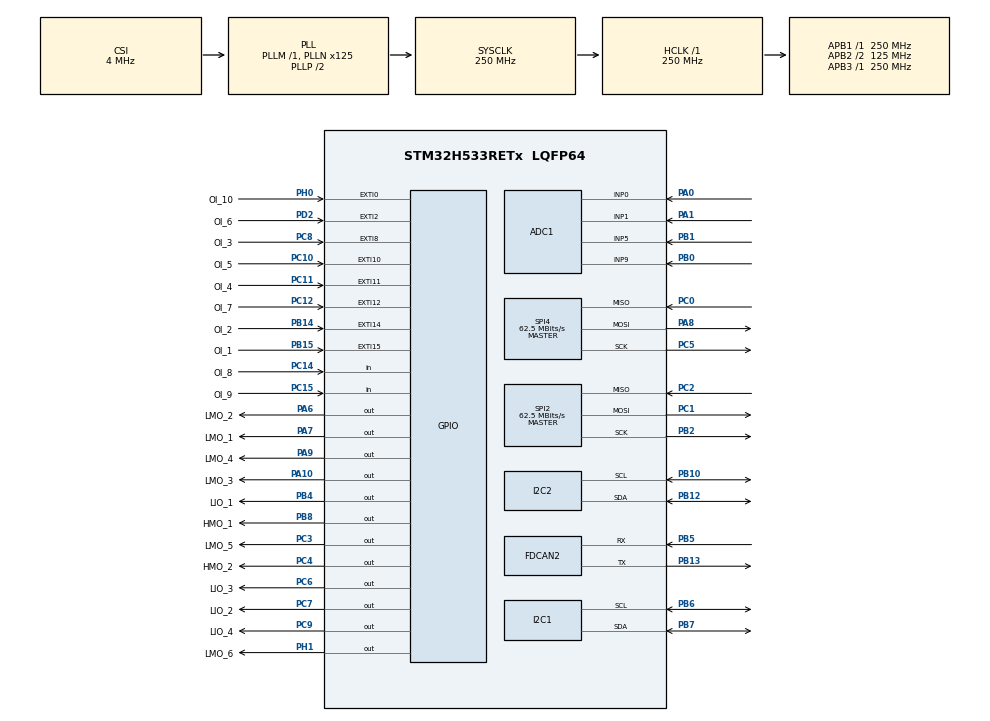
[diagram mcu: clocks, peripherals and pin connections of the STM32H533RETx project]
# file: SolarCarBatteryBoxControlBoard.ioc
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ADC1.Channel-2\#ChannelRegularConversion=ADC_CHANNEL_0
ADC1.Channel-3\#ChannelRegularConversion=ADC_CHANNEL_1
ADC1.Channel-4\#ChannelRegularConversion=ADC_CHANNEL_5
ADC1.Channel-5\#ChannelRegularConversion=ADC_CHANNEL_9
ADC1.DiscontinuousConvMode=DISABLE
ADC1.EOCSelection=ADC_EOC_SEQ_CONV
ADC1.EnableAnalogWatchDog1=false
ADC1.ExternalTrigConv=ADC_SOFTWARE_START
ADC1.MonitoredBy-2\#ChannelRegularConversion=__NULL
ADC1.MonitoredBy-3\#ChannelRegularConversion=__NULL
ADC1.MonitoredBy-4\#ChannelRegularConversion=__NULL
ADC1.MonitoredBy-5\#ChannelRegularConversion=__NULL
ADC1.NbrOfConversion=4
ADC1.NbrOfConversionFlag=1
ADC1.OffsetNumber-2\#ChannelRegularConversion=ADC_OFFSET_NONE
ADC1.OffsetNumber-3\#ChannelRegularConversion=ADC_OFFSET_NONE
ADC1.OffsetNumber-4\#ChannelRegularConversion=ADC_OFFSET_NONE
ADC1.OffsetNumber-5\#ChannelRegularConversion=ADC_OFFSET_NONE
ADC1.Overrun=ADC_OVR_DATA_PRESERVED
ADC1.OversamplingMode=DISABLE
ADC1.Rank-2\#ChannelRegularConversion=1
ADC1.Rank-3\#ChannelRegularConversion=2
ADC1.Rank-4\#ChannelRegularConversion=3
ADC1.Rank-5\#ChannelRegularConversion=4
ADC1.SamplingTime-2\#ChannelRegularConversion=ADC_SAMPLETIME_24CYCLES_5
ADC1.SamplingTime-3\#ChannelRegularConversion=ADC_SAMPLETIME_24CYCLES_5
ADC1.SamplingTime-4\#ChannelRegularConversion=ADC_SAMPLETIME_24CYCLES_5
ADC1.SamplingTime-5\#ChannelRegularConversion=ADC_SAMPLETIME_24CYCLES_5
ADC1.master=1
BOOTPATH.BootPathName=LEGACY
BOOTPATH.UserSelectedBootPath=LEGACY
CORTEX_M33_NS.Enable-Cortex_Memory_Protection_Unit_Region0_Settings=__NULL
CORTEX_M33_NS.MPU_Control=__NULL
CORTEX_M33_NS.Number-Cortex_Memory_Protection_Unit_Region0_Settings=MPU_REGION_NUMBER0
CORTEX_M33_NS.userName=CORTEX_M33
FDCAN2.AutoRetransmission=ENABLE
FDCAN2.CalculateBaudRateNominal=500000
FDCAN2.CalculateTimeBitNominal=2000
FDCAN2.CalculateTimeQuantumNominal=250.0
FDCAN2.FrameFormat=FDCAN_FRAME_FD_NO_BRS
FDCAN2.Mode=FDCAN_MODE_NORMAL
FDCAN2.NominalPrescaler=32
FDCAN2.NominalTimeSeg1=6
FDCAN2.NominalTimeSeg2=1
FDCAN2.StdFiltersNbr=0
GPDMA1.CIRCULARMODE_GPDMACH0=ENABLE
GPDMA1.DATAHANDLING_GPDMACH0=NONE
GPDMA1.DESTDATAWIDTH_GPDMACH0=DMA_DEST_DATAWIDTH_HALFWORD
GPDMA1.DESTINC_GPDMACH0=DMA_DINC_INCREMENTED
GPDMA1.IPHANDLE_GPDMACH0-SIMPLEREQUEST_GPDMACH0=__NULL
GPDMA1.REQUEST_GPDMACH0=GPDMA1_REQUEST_ADC1
GPDMA1.SRCDATAWIDTH_GPDMACH0=DMA_SRC_DATAWIDTH_HALFWORD
GPDMA1.TRIGGERPOLARITY_GPDMACH0=DMA_TRIG_POLARITY_MASKED
I2C1.Timing=0x60808CD3
I2C2.Timing=0x60808CD3
Mcu.Family=STM32H5
Mcu.Name=STM32H533RETx
Mcu.Package=LQFP64
NUCLEO-H533RE.BUTTON=1
NUCLEO-H533RE.LD4=true
NUCLEO-H533RE.VCP=true
NVIC.EXTI0_IRQn=true\:2\:0\:true\:false\:true\:true\:true\:true
NVIC.EXTI10_IRQn=true\:2\:0\:true\:false\:true\:true\:true\:true
NVIC.EXTI11_IRQn=true\:2\:0\:true\:false\:true\:true\:true\:true
NVIC.EXTI12_IRQn=true\:2\:0\:true\:false\:true\:true\:true\:true
NVIC.EXTI13_IRQn=true\:2\:0\:true\:false\:true\:true\:true\:true
NVIC.EXTI14_IRQn=true\:2\:0\:true\:false\:true\:true\:true\:true
NVIC.EXTI15_IRQn=true\:2\:0\:true\:false\:true\:true\:true\:true
NVIC.EXTI2_IRQn=true\:2\:0\:true\:false\:true\:true\:true\:true
NVIC.EXTI8_IRQn=true\:2\:0\:true\:false\:true\:true\:true\:true
NVIC.FDCAN2_IT0_IRQn=true\:2\:0\:true\:false\:true\:true\:true\:true
NVIC.GPDMA1_Channel0_IRQn=true\:0\:0\:false\:false\:true\:false\:true\:true
NVIC.I2C1_ER_IRQn=true\:0\:0\:false\:false\:true\:true\:true\:true
NVIC.I2C1_EV_IRQn=true\:0\:0\:true\:false\:true\:true\:true\:true
NVIC.PriorityGroup=NVIC_PRIORITYGROUP_4
PA0.Signal=ADCx_INP0
PA1.Signal=ADCx_INP1
PA10.GPIO_Label=LMO_3
PA10.Signal=GPIO_Output
PA13(JTMS/SWDIO).GPIO_Label=SWDIO
PA13(JTMS/SWDIO).Signal=DEBUG_JTMS-SWDIO
PA14(JTCK/SWCLK).GPIO_Label=SWCLK
PA14(JTCK/SWCLK).Signal=DEBUG_JTCK-SWCLK
PA15(JTDI).GPIO_Label=JTDI
PA15(JTDI).Signal=DEBUG_JTDI
PA2.Signal=USART2_TX
PA3.Signal=USART2_RX
PA6.GPIO_Label=LMO_2
PA6.Signal=GPIO_Output
PA7.GPIO_Label=LMO_1
PA7.Signal=GPIO_Output
PA8.GPIO_Speed=GPIO_SPEED_FREQ_VERY_HIGH
PA8.Mode=Full_Duplex_Master
PA8.Signal=SPI4_MOSI
PA9.GPIO_Label=LMO_4
PA9.Signal=GPIO_Output
PB0.Signal=ADCx_INP9
PB1.Signal=ADCx_INP5
PB10.GPIO_Pu=GPIO_PULLUP
PB10.GPIO_Speed=GPIO_SPEED_FREQ_VERY_HIGH
PB10.Mode=I2C
PB10.Signal=I2C2_SCL
PB12.GPIO_Pu=GPIO_PULLUP
PB12.GPIO_Speed=GPIO_SPEED_FREQ_VERY_HIGH
PB12.Mode=I2C
PB12.Signal=I2C2_SDA
PB13.GPIO_Speed=GPIO_SPEED_FREQ_VERY_HIGH
PB13.Mode=FDCAN_Activate
PB13.Signal=FDCAN2_TX
PB14.GPIO_Label=OI_2
PB14.GPIO_ModeDefaultEXTI=GPIO_MODE_IT_RISING_FALLING
PB14.Signal=GPXTI14
PB15.GPIO_Label=OI_1
PB15.GPIO_ModeDefaultEXTI=GPIO_MODE_IT_RISING_FALLING
PB15.GPIO_PuPd=GPIO_NOPULL
PB15.Signal=GPXTI15
PB2.GPIO_Speed=GPIO_SPEED_FREQ_VERY_HIGH
PB2.Mode=Full_Duplex_Master
PB2.Signal=SPI2_SCK
PB3(JTDO/TRACESWO).GPIO_Label=SWO
PB3(JTDO/TRACESWO).Signal=DEBUG_JTDO-SWO
PB4(NJTRST).GPIO_Label=LIO_1
PB4(NJTRST).Signal=GPIO_Output
PB5.GPIO_PuPd=GPIO_PULLUP
PB5.GPIO_Speed=GPIO_SPEED_FREQ_VERY_HIGH
PB5.Mode=FDCAN_Activate
PB5.Signal=FDCAN2_RX
PB6.GPIO_Pu=GPIO_PULLUP
PB6.GPIO_Speed=GPIO_SPEED_FREQ_VERY_HIGH
PB6.Mode=I2C
PB6.Signal=I2C1_SCL
PB7.GPIO_Pu=GPIO_PULLUP
PB7.GPIO_Speed=GPIO_SPEED_FREQ_VERY_HIGH
PB7.Mode=I2C
PB7.Signal=I2C1_SDA
PB8.GPIO_Label=HMO_1
PB8.GPIO_PuPd=GPIO_PULLUP
PB8.PinState=GPIO_PIN_SET
PB8.Signal=GPIO_Output
PC0.GPIO_Speed=GPIO_SPEED_FREQ_VERY_HIGH
PC0.Mode=Full_Duplex_Master
PC0.Signal=SPI4_MISO
PC1.GPIO_Speed=GPIO_SPEED_FREQ_VERY_HIGH
PC1.Mode=Full_Duplex_Master
PC1.Signal=SPI2_MOSI
PC10.GPIO_Label=OI_5
PC10.GPIO_ModeDefaultEXTI=GPIO_MODE_IT_RISING_FALLING
PC10.Signal=GPXTI10
PC11.GPIO_Label=OI_4
PC11.GPIO_ModeDefaultEXTI=GPIO_MODE_IT_RISING_FALLING
PC11.Signal=GPXTI11
PC12.GPIO_Label=OI_7
PC12.GPIO_ModeDefaultEXTI=GPIO_MODE_IT_RISING_FALLING
PC12.Signal=GPXTI12
PC14-OSC32_IN(OSC32_IN).GPIO_Label=OI_8
PC14-OSC32_IN(OSC32_IN).Signal=GPIO_Input
PC15-OSC32_OUT(OSC32_OUT).GPIO_Label=OI_9
PC15-OSC32_OUT(OSC32_OUT).Signal=GPIO_Input
PC2.GPIO_Speed=GPIO_SPEED_FREQ_VERY_HIGH
PC2.Mode=Full_Duplex_Master
PC2.Signal=SPI2_MISO
PC3.GPIO_Label=LMO_5
PC3.Signal=GPIO_Output
PC4.GPIO_Label=HMO_2
PC4.GPIO_PuPd=GPIO_PULLUP
PC4.PinState=GPIO_PIN_SET
PC4.Signal=GPIO_Output
PC5.GPIO_Speed=GPIO_SPEED_FREQ_VERY_HIGH
PC5.Mode=Full_Duplex_Master
PC5.Signal=SPI4_SCK
PC6.GPIO_Label=LIO_3
PC6.Signal=GPIO_Output
PC7.GPIO_Label=LIO_2
PC7.Signal=GPIO_Output
PC8.GPIO_Label=OI_3
PC8.GPIO_ModeDefaultEXTI=GPIO_MODE_IT_RISING_FALLING
PC8.GPIO_PuPd=GPIO_NOPULL
PC8.Signal=GPXTI8
PC9.GPIO_Label=LIO_4
PC9.Signal=GPIO_Output
PD2.GPIO_Label=OI_6
PD2.GPIO_ModeDefaultEXTI=GPIO_MODE_IT_RISING_FALLING
PD2.Signal=GPXTI2
PH0-OSC_IN(PH0).GPIO_Label=OI_10
PH0-OSC_IN(PH0).GPIO_ModeDefaultEXTI=GPIO_MODE_IT_RISING_FALLING
PH0-OSC_IN(PH0).Signal=GPXTI0
PH1-OSC_OUT(PH1).GPIO_Label=LMO_6
PH1-OSC_OUT(PH1).Signal=GPIO_Output
ProjectManager.HeapSize=0x200
ProjectManager.StackSize=0x400
ProjectManager.TargetToolchain=CMake
RCC.ADCFreq_Value=250000000
RCC.AHBFreq_Value=250000000
RCC.APB1Freq_Value=250000000
RCC.APB1TimFreq_Value=250000000
RCC.APB2CLKDivider=RCC_HCLK_DIV2
RCC.APB2Freq_Value=125000000
RCC.APB2TimFreq_Value=250000000
RCC.APB3Freq_Value=250000000
RCC.CSI_VALUE=4000000
RCC.CortexFreq_Value=250000000
RCC.EPOD_VALUE=4000000
RCC.FDCANClockSelection=RCC_FDCANCLKSOURCE_PLL2Q
RCC.HCLKFreq_Value=250000000
RCC.HSE_VALUE=25000000
RCC.HSI48_VALUE=48000000
RCC.HSIDiv=RCC_HSI_DIV1
RCC.HSI_VALUE=64000000
RCC.LSE_VALUE=32768
RCC.LSIRC_VALUE=32000
RCC.PLL1Q=4
RCC.PLL2FRACN=0
RCC.PLL2N=32
RCC.PLL2Q=1
RCC.PLL3N=128
RCC.PLLFRACN=0
RCC.PLLN=125
RCC.SYSCLKFreq_VALUE=250000000
RCC.SYSCLKSource=RCC_SYSCLKSOURCE_PLLCLK
RCC.USBFreq_Value=48000000
RCC.VCOOutputFreq_Value=500000000
SH.ADCx_INP0.0=ADC1_INP0,IN0-Single-Ended
SH.ADCx_INP1.0=ADC1_INP1,IN1-Single-Ended
SH.ADCx_INP5.0=ADC1_INP5,IN5-Single-Ended
SH.ADCx_INP9.0=ADC1_INP9,IN9-Single-Ended
SPI2.BaudRatePrescaler=SPI_BAUDRATEPRESCALER_2
SPI2.CalculateBaudRate=62.5 MBits/s
SPI2.Direction=SPI_DIRECTION_2LINES
SPI2.Mode=SPI_MODE_MASTER
SPI2.VirtualType=VM_MASTER
SPI4.CalculateBaudRate=62.5 MBits/s
SPI4.Direction=SPI_DIRECTION_2LINES
SPI4.Mode=SPI_MODE_MASTER
SPI4.VirtualType=VM_MASTER
VP_BOOTPATH_VS_BOOTPATH.Mode=BP_Activate
VP_CORTEX_M33_NS_VS_Hclk.Mode=Hclk_Mode
VP_GPDMA1_VS_GPDMACH0.Mode=SIMPLEREQUEST_GPDMACH0
VP_ICACHE_VS_ICACHE.Mode=DefaultMode
VP_MEMORYMAP_VS_MEMORYMAP.Mode=CurAppReg
VP_NUCLEO-H533RE_VS_BSP_COMMON.Mode=COMMON
VP_PWR_VS_LPOM.Mode=PowerOptimisation
VP_PWR_VS_SECSignals.Mode=Security/Privilege
board=NUCLEO-H533RE

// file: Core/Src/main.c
/* USER CODE BEGIN Header */
/**
 ******************************************************************************
 * @file           : main.c
 * @brief          : Main program body
 ******************************************************************************
 * @attention
 *
 * Copyright (c) 2026 STMicroelectronics.
 * All rights reserved.
 *
 * This software is licensed under terms that can be found in the LICENSE file
 * in the root directory of this software component.
 * If no LICENSE file comes with this software, it is provided AS-IS.
 *
 ******************************************************************************
 */
/* USER CODE END Header */
#include "main.h"

/* USER CODE BEGIN Includes */
#include "stm32h5xx_hal.h"
#include "stm32h5xx_hal_fdcan.h"
#include "stm32h5xx_nucleo.h"
#include "ws_can_comms.h"
#include <stdint.h>
#include <string.h>
/* USER CODE END Includes */

COM_InitTypeDef BspCOMInit;
ADC_HandleTypeDef hadc1;

FDCAN_HandleTypeDef hfdcan2;

I2C_HandleTypeDef hi2c1;
I2C_HandleTypeDef hi2c2;

SPI_HandleTypeDef hspi2;
SPI_HandleTypeDef hspi4;

void SystemClock_Config(void);
static void MX_GPIO_Init(void);
static void MX_FDCAN2_Init(void);
static void MX_I2C1_Init(void);
static void MX_I2C2_Init(void);
static void MX_SPI2_Init(void);
static void MX_SPI4_Init(void);
static void MX_ICACHE_Init(void);
static void MX_ADC1_Init(void);

/* USER CODE BEGIN 0 */

// FDCAN2 Defines
FDCAN_TxHeaderTypeDef txHeader;
FDCAN_RxHeaderTypeDef rxHeader;
uint8_t txData[64];
uint8_t rxData[8];

void HAL_FDCAN_RxFifo0Callback(FDCAN_HandleTypeDef *hfdcan,
                               uint32_t RxFifo0ITs) {
  if ((RxFifo0ITs & FDCAN_IT_RX_FIFO0_NEW_MESSAGE) != RESET) {
    /* Retreive Rx messages from RX FIFO0 */
    if (HAL_FDCAN_GetRxMessage(hfdcan, FDCAN_RX_FIFO0, &rxHeader, rxData) !=
        HAL_OK) {
      /* Reception Error */
      Error_Handler();
    }
    if (HAL_FDCAN_ActivateNotification(hfdcan, FDCAN_IT_RX_FIFO0_NEW_MESSAGE,
                                       0) != HAL_OK) {
      /* Notification Error */
      Error_Handler();
    }

    // Just for testing purposes
    uint32_t data1, data2;
    memcpy(&data1, &rxData[0], sizeof(data1));
    memcpy(&data2, &rxData[4], sizeof(data2));

    printf("\n\nID:0x%x/n%.8lx 0x%.8lx\n\n",rxHeader.Identifier, data1, data2);
  }
}

/* USER CODE END 0 */

int main(void) {

  /* MCU Configuration--------------------------------------------------------*/

  /* Reset of all peripherals, Initializes the Flash interface and the Systick.
   */
  HAL_Init();

  /* Configure the system clock */
  SystemClock_Config();

  /* Initialize all configured peripherals */
  MX_GPIO_Init();
  MX_FDCAN2_Init();
  MX_I2C1_Init();
  MX_I2C2_Init();
  MX_SPI2_Init();
  MX_SPI4_Init();
  MX_ICACHE_Init();
  MX_ADC1_Init();
  /* USER CODE BEGIN 2 */

  // Start FDCAN2
  if (HAL_FDCAN_Start(&hfdcan2) != HAL_OK) {
    Error_Handler();
  }
  // Activate FIFO0 reciept notification
  if (HAL_FDCAN_ActivateNotification(&hfdcan2, FDCAN_IT_RX_FIFO0_NEW_MESSAGE,
                                     0) != HAL_OK) {
    /* Notification Error */
    Error_Handler();
  }

  // Configure TX Header for FDCAN2
  txHeader.Identifier = 0x11;
  txHeader.IdType = FDCAN_STANDARD_ID;
  txHeader.TxFrameType = FDCAN_DATA_FRAME;
  txHeader.DataLength = FDCAN_DLC_BYTES_8;
  txHeader.ErrorStateIndicator = FDCAN_ESI_ACTIVE;
  txHeader.BitRateSwitch = FDCAN_BRS_OFF;
  txHeader.FDFormat = FDCAN_CLASSIC_CAN;
  txHeader.TxEventFifoControl = FDCAN_NO_TX_EVENTS;
  txHeader.MessageMarker = 0;

  /* USER CODE END 2 */

  /* Initialize leds */
  BSP_LED_Init(LED_GREEN);

  /* Initialize USER push-button, will be used to trigger an interrupt each time
   * it's pressed.*/
  BSP_PB_Init(BUTTON_USER, BUTTON_MODE_EXTI);

  /* Initialize COM1 port (115200, 8 bits (7-bit data + 1 stop bit), no parity
   */
  BspCOMInit.BaudRate = 115200;
  BspCOMInit.WordLength = COM_WORDLENGTH_8B;
  BspCOMInit.StopBits = COM_STOPBITS_1;
  BspCOMInit.Parity = COM_PARITY_NONE;
  BspCOMInit.HwFlowCtl = COM_HWCONTROL_NONE;
  if (BSP_COM_Init(COM1, &BspCOMInit) != BSP_ERROR_NONE) {
    Error_Handler();
  }

  /* Infinite loop */
  while (1) {

    /* USER CODE BEGIN 3 */
    // Blink to show alive
    BSP_LED_Toggle(LED_GREEN);

    WS_RequestIdentificationInformation(&hfdcan2);
    // Should result in the serial number and Prohelion ID being sent to CAN Bus
    // After the message is received, the expected output is:
    // <Serial number>
    // 0x00004003 (Prohelion ID)

    HAL_Delay(2500);
    // Blink to show alive
    BSP_LED_Toggle(LED_GREEN);
    HAL_Delay(2500);
  }
  /* USER CODE END 3 */
}

void SystemClock_Config(void) {
  RCC_OscInitTypeDef RCC_OscInitStruct = {0};
  RCC_ClkInitTypeDef RCC_ClkInitStruct = {0};

  /** Configure the main internal regulator output voltage
   */
  __HAL_PWR_VOLTAGESCALING_CONFIG(PWR_REGULATOR_VOLTAGE_SCALE0);

  while (!__HAL_PWR_GET_FLAG(PWR_FLAG_VOSRDY)) {
  }

  /** Initializes the RCC Oscillators according to the specified parameters
   * in the RCC_OscInitTypeDef structure.
   */
  RCC_OscInitStruct.OscillatorType = RCC_OSCILLATORTYPE_CSI;
  RCC_OscInitStruct.CSIState = RCC_CSI_ON;
  RCC_OscInitStruct.CSICalibrationValue = RCC_CSICALIBRATION_DEFAULT;
  RCC_OscInitStruct.PLL.PLLState = RCC_PLL_ON;
  RCC_OscInitStruct.PLL.PLLSource = RCC_PLL1_SOURCE_CSI;
  RCC_OscInitStruct.PLL.PLLM = 1;
  RCC_OscInitStruct.PLL.PLLN = 125;
  RCC_OscInitStruct.PLL.PLLP = 2;
  RCC_OscInitStruct.PLL.PLLQ = 4;
  RCC_OscInitStruct.PLL.PLLR = 2;
  RCC_OscInitStruct.PLL.PLLRGE = RCC_PLL1_VCIRANGE_2;
  RCC_OscInitStruct.PLL.PLLVCOSEL = RCC_PLL1_VCORANGE_WIDE;
  RCC_OscInitStruct.PLL.PLLFRACN = 0;
  if (HAL_RCC_OscConfig(&RCC_OscInitStruct) != HAL_OK) {
    Error_Handler();
  }

  /** Initializes the CPU, AHB and APB buses clocks
   */
  RCC_ClkInitStruct.ClockType = RCC_CLOCKTYPE_HCLK | RCC_CLOCKTYPE_SYSCLK |
                                RCC_CLOCKTYPE_PCLK1 | RCC_CLOCKTYPE_PCLK2 |
                                RCC_CLOCKTYPE_PCLK3;
  RCC_ClkInitStruct.SYSCLKSource = RCC_SYSCLKSOURCE_PLLCLK;
  RCC_ClkInitStruct.AHBCLKDivider = RCC_SYSCLK_DIV1;
  RCC_ClkInitStruct.APB1CLKDivider = RCC_HCLK_DIV1;
  RCC_ClkInitStruct.APB2CLKDivider = RCC_HCLK_DIV2;
  RCC_ClkInitStruct.APB3CLKDivider = RCC_HCLK_DIV1;

  if (HAL_RCC_ClockConfig(&RCC_ClkInitStruct, FLASH_LATENCY_5) != HAL_OK) {
    Error_Handler();
  }

  /** Configure the programming delay
   */
  __HAL_FLASH_SET_PROGRAM_DELAY(FLASH_PROGRAMMING_DELAY_2);
}

static void MX_ADC1_Init(void) {

  ADC_ChannelConfTypeDef sConfig = {0};

  /** Common config
   */
  hadc1.Instance = ADC1;
  hadc1.Init.ClockPrescaler = ADC_CLOCK_ASYNC_DIV4;
  hadc1.Init.Resolution = ADC_RESOLUTION_12B;
  hadc1.Init.DataAlign = ADC_DATAALIGN_RIGHT;
  hadc1.Init.ScanConvMode = ADC_SCAN_DISABLE;
  hadc1.Init.EOCSelection = ADC_EOC_SINGLE_CONV;
  hadc1.Init.LowPowerAutoWait = DISABLE;
  hadc1.Init.ContinuousConvMode = DISABLE;
  hadc1.Init.NbrOfConversion = 1;
  hadc1.Init.DiscontinuousConvMode = DISABLE;
  hadc1.Init.ExternalTrigConv = ADC_SOFTWARE_START;
  hadc1.Init.ExternalTrigConvEdge = ADC_EXTERNALTRIGCONVEDGE_NONE;
  hadc1.Init.DMAContinuousRequests = DISABLE;
  hadc1.Init.SamplingMode = ADC_SAMPLING_MODE_NORMAL;
  hadc1.Init.Overrun = ADC_OVR_DATA_PRESERVED;
  hadc1.Init.OversamplingMode = DISABLE;
  if (HAL_ADC_Init(&hadc1) != HAL_OK) {
    Error_Handler();
  }

  /** Configure Regular Channel
   */
  sConfig.Channel = ADC_CHANNEL_1;
  sConfig.Rank = ADC_REGULAR_RANK_1;
  sConfig.SamplingTime = ADC_SAMPLETIME_2CYCLES_5;
  sConfig.SingleDiff = ADC_SINGLE_ENDED;
  sConfig.OffsetNumber = ADC_OFFSET_NONE;
  sConfig.Offset = 0;
  if (HAL_ADC_ConfigChannel(&hadc1, &sConfig) != HAL_OK) {
    Error_Handler();
  }
}

static void MX_FDCAN2_Init(void) {

  hfdcan2.Instance = FDCAN2;
  hfdcan2.Init.ClockDivider = FDCAN_CLOCK_DIV1;
  hfdcan2.Init.FrameFormat = FDCAN_FRAME_FD_NO_BRS;
  hfdcan2.Init.Mode = FDCAN_MODE_NORMAL;
  hfdcan2.Init.AutoRetransmission = ENABLE;
  hfdcan2.Init.TransmitPause = DISABLE;
  hfdcan2.Init.ProtocolException = DISABLE;
  hfdcan2.Init.NominalPrescaler = 32;
  hfdcan2.Init.NominalSyncJumpWidth = 1;
  hfdcan2.Init.NominalTimeSeg1 = 6;
  hfdcan2.Init.NominalTimeSeg2 = 1;
  hfdcan2.Init.DataPrescaler = 1;
  hfdcan2.Init.DataSyncJumpWidth = 1;
  hfdcan2.Init.DataTimeSeg1 = 1;
  hfdcan2.Init.DataTimeSeg2 = 1;
  hfdcan2.Init.StdFiltersNbr = 0;
  hfdcan2.Init.ExtFiltersNbr = 0;
  hfdcan2.Init.TxFifoQueueMode = FDCAN_TX_FIFO_OPERATION;
  if (HAL_FDCAN_Init(&hfdcan2) != HAL_OK) {
    Error_Handler();
  }
}

static void MX_I2C1_Init(void) {

  hi2c1.Instance = I2C1;
  hi2c1.Init.Timing = 0x60808CD3;
  hi2c1.Init.OwnAddress1 = 0;
  hi2c1.Init.AddressingMode = I2C_ADDRESSINGMODE_7BIT;
  hi2c1.Init.DualAddressMode = I2C_DUALADDRESS_DISABLE;
  hi2c1.Init.OwnAddress2 = 0;
  hi2c1.Init.OwnAddress2Masks = I2C_OA2_NOMASK;
  hi2c1.Init.GeneralCallMode = I2C_GENERALCALL_DISABLE;
  hi2c1.Init.NoStretchMode = I2C_NOSTRETCH_DISABLE;
  if (HAL_I2C_Init(&hi2c1) != HAL_OK) {
    Error_Handler();
  }

  /** Configure Analogue filter
   */
  if (HAL_I2CEx_ConfigAnalogFilter(&hi2c1, I2C_ANALOGFILTER_ENABLE) != HAL_OK) {
    Error_Handler();
  }

  /** Configure Digital filter
   */
  if (HAL_I2CEx_ConfigDigitalFilter(&hi2c1, 0) != HAL_OK) {
    Error_Handler();
  }
}

static void MX_I2C2_Init(void) {

  hi2c2.Instance = I2C2;
  hi2c2.Init.Timing = 0x60808CD3;
  hi2c2.Init.OwnAddress1 = 0;
  hi2c2.Init.AddressingMode = I2C_ADDRESSINGMODE_7BIT;
  hi2c2.Init.DualAddressMode = I2C_DUALADDRESS_DISABLE;
  hi2c2.Init.OwnAddress2 = 0;
  hi2c2.Init.OwnAddress2Masks = I2C_OA2_NOMASK;
  hi2c2.Init.GeneralCallMode = I2C_GENERALCALL_DISABLE;
  hi2c2.Init.NoStretchMode = I2C_NOSTRETCH_DISABLE;
  if (HAL_I2C_Init(&hi2c2) != HAL_OK) {
    Error_Handler();
  }

  /** Configure Analogue filter
   */
  if (HAL_I2CEx_ConfigAnalogFilter(&hi2c2, I2C_ANALOGFILTER_ENABLE) != HAL_OK) {
    Error_Handler();
  }

  /** Configure Digital filter
   */
  if (HAL_I2CEx_ConfigDigitalFilter(&hi2c2, 0) != HAL_OK) {
    Error_Handler();
  }
}

static void MX_ICACHE_Init(void) {

}

static void MX_SPI2_Init(void) {

  /* SPI2 parameter configuration*/
  hspi2.Instance = SPI2;
  hspi2.Init.Mode = SPI_MODE_MASTER;
  hspi2.Init.Direction = SPI_DIRECTION_2LINES;
  hspi2.Init.DataSize = SPI_DATASIZE_4BIT;
  hspi2.Init.CLKPolarity = SPI_POLARITY_LOW;
  hspi2.Init.CLKPhase = SPI_PHASE_1EDGE;
  hspi2.Init.NSS = SPI_NSS_SOFT;
  hspi2.Init.BaudRatePrescaler = SPI_BAUDRATEPRESCALER_2;
  hspi2.Init.FirstBit = SPI_FIRSTBIT_MSB;
  hspi2.Init.TIMode = SPI_TIMODE_DISABLE;
  hspi2.Init.CRCCalculation = SPI_CRCCALCULATION_DISABLE;
  hspi2.Init.CRCPolynomial = 0x7;
  hspi2.Init.NSSPMode = SPI_NSS_PULSE_ENABLE;
  hspi2.Init.NSSPolarity = SPI_NSS_POLARITY_LOW;
  hspi2.Init.FifoThreshold = SPI_FIFO_THRESHOLD_01DATA;
  hspi2.Init.MasterSSIdleness = SPI_MASTER_SS_IDLENESS_00CYCLE;
  hspi2.Init.MasterInterDataIdleness = SPI_MASTER_INTERDATA_IDLENESS_00CYCLE;
  hspi2.Init.MasterReceiverAutoSusp = SPI_MASTER_RX_AUTOSUSP_DISABLE;
  hspi2.Init.MasterKeepIOState = SPI_MASTER_KEEP_IO_STATE_DISABLE;
  hspi2.Init.IOSwap = SPI_IO_SWAP_DISABLE;
  hspi2.Init.ReadyMasterManagement = SPI_RDY_MASTER_MANAGEMENT_INTERNALLY;
  hspi2.Init.ReadyPolarity = SPI_RDY_POLARITY_HIGH;
  if (HAL_SPI_Init(&hspi2) != HAL_OK) {
    Error_Handler();
  }
}

static void MX_SPI4_Init(void) {

  /* SPI4 parameter configuration*/
  hspi4.Instance = SPI4;
  hspi4.Init.Mode = SPI_MODE_MASTER;
  hspi4.Init.Direction = SPI_DIRECTION_2LINES;
  hspi4.Init.DataSize = SPI_DATASIZE_4BIT;
  hspi4.Init.CLKPolarity = SPI_POLARITY_LOW;
  hspi4.Init.CLKPhase = SPI_PHASE_1EDGE;
  hspi4.Init.NSS = SPI_NSS_SOFT;
  hspi4.Init.BaudRatePrescaler = SPI_BAUDRATEPRESCALER_2;
  hspi4.Init.FirstBit = SPI_FIRSTBIT_MSB;
  hspi4.Init.TIMode = SPI_TIMODE_DISABLE;
  hspi4.Init.CRCCalculation = SPI_CRCCALCULATION_DISABLE;
  hspi4.Init.CRCPolynomial = 0x7;
  hspi4.Init.NSSPMode = SPI_NSS_PULSE_ENABLE;
  hspi4.Init.NSSPolarity = SPI_NSS_POLARITY_LOW;
  hspi4.Init.FifoThreshold = SPI_FIFO_THRESHOLD_01DATA;
  hspi4.Init.MasterSSIdleness = SPI_MASTER_SS_IDLENESS_00CYCLE;
  hspi4.Init.MasterInterDataIdleness = SPI_MASTER_INTERDATA_IDLENESS_00CYCLE;
  hspi4.Init.MasterReceiverAutoSusp = SPI_MASTER_RX_AUTOSUSP_DISABLE;
  hspi4.Init.MasterKeepIOState = SPI_MASTER_KEEP_IO_STATE_DISABLE;
  hspi4.Init.IOSwap = SPI_IO_SWAP_DISABLE;
  hspi4.Init.ReadyMasterManagement = SPI_RDY_MASTER_MANAGEMENT_INTERNALLY;
  hspi4.Init.ReadyPolarity = SPI_RDY_POLARITY_HIGH;
  if (HAL_SPI_Init(&hspi4) != HAL_OK) {
    Error_Handler();
  }
}

static void MX_GPIO_Init(void) {
  GPIO_InitTypeDef GPIO_InitStruct = {0};

  /* GPIO Ports Clock Enable */
  __HAL_RCC_GPIOC_CLK_ENABLE();
  __HAL_RCC_GPIOH_CLK_ENABLE();
  __HAL_RCC_GPIOA_CLK_ENABLE();
  __HAL_RCC_GPIOB_CLK_ENABLE();
  __HAL_RCC_GPIOD_CLK_ENABLE();

  /*Configure GPIO pin Output Level */
  HAL_GPIO_WritePin(LO_10_GPIO_Port, LO_10_Pin, GPIO_PIN_RESET);

  /*Configure GPIO pin Output Level */
  HAL_GPIO_WritePin(GPIOC, LO_9_Pin | HO_2_Pin | LO_3_Pin | LO_2_Pin | LO_4_Pin,
                    GPIO_PIN_RESET);

  /*Configure GPIO pin Output Level */
  HAL_GPIO_WritePin(GPIOA, LO_6_Pin | LO_5_Pin | LO_8_Pin | LO_7_Pin,
                    GPIO_PIN_RESET);

  /*Configure GPIO pin Output Level */
  HAL_GPIO_WritePin(GPIOB, LO_4B4_Pin | HO_1_Pin, GPIO_PIN_RESET);

  /*Configure GPIO pins : OI_8_Pin OI_9_Pin OI_5_Pin OI_4_Pin
                           OI_7_Pin */
  GPIO_InitStruct.Pin = OI_8_Pin | OI_9_Pin | OI_5_Pin | OI_4_Pin | OI_7_Pin;
  GPIO_InitStruct.Mode = GPIO_MODE_INPUT;
  GPIO_InitStruct.Pull = GPIO_NOPULL;
  HAL_GPIO_Init(GPIOC, &GPIO_InitStruct);

  /*Configure GPIO pin : OI_10_Pin */
  GPIO_InitStruct.Pin = OI_10_Pin;
  GPIO_InitStruct.Mode = GPIO_MODE_INPUT;
  GPIO_InitStruct.Pull = GPIO_NOPULL;
  HAL_GPIO_Init(OI_10_GPIO_Port, &GPIO_InitStruct);

  /*Configure GPIO pin : LO_10_Pin */
  GPIO_InitStruct.Pin = LO_10_Pin;
  GPIO_InitStruct.Mode = GPIO_MODE_OUTPUT_PP;
  GPIO_InitStruct.Pull = GPIO_NOPULL;
  GPIO_InitStruct.Speed = GPIO_SPEED_FREQ_LOW;
  HAL_GPIO_Init(LO_10_GPIO_Port, &GPIO_InitStruct);

  /*Configure GPIO pins : LO_9_Pin HO_2_Pin LO_3_Pin LO_2_Pin
                           LO_4_Pin */
  GPIO_InitStruct.Pin = LO_9_Pin | HO_2_Pin | LO_3_Pin | LO_2_Pin | LO_4_Pin;
  GPIO_InitStruct.Mode = GPIO_MODE_OUTPUT_PP;
  GPIO_InitStruct.Pull = GPIO_NOPULL;
  GPIO_InitStruct.Speed = GPIO_SPEED_FREQ_LOW;
  HAL_GPIO_Init(GPIOC, &GPIO_InitStruct);

  /*Configure GPIO pins : LO_6_Pin LO_5_Pin LO_8_Pin LO_7_Pin */
  GPIO_InitStruct.Pin = LO_6_Pin | LO_5_Pin | LO_8_Pin | LO_7_Pin;
  GPIO_InitStruct.Mode = GPIO_MODE_OUTPUT_PP;
  GPIO_InitStruct.Pull = GPIO_NOPULL;
  GPIO_InitStruct.Speed = GPIO_SPEED_FREQ_LOW;
  HAL_GPIO_Init(GPIOA, &GPIO_InitStruct);

  /*Configure GPIO pins : OI_2_Pin OI_1_Pin */
  GPIO_InitStruct.Pin = OI_2_Pin | OI_1_Pin;
  GPIO_InitStruct.Mode = GPIO_MODE_IT_RISING;
  GPIO_InitStruct.Pull = GPIO_NOPULL;
  HAL_GPIO_Init(GPIOB, &GPIO_InitStruct);

  /*Configure GPIO pin : OI_3_Pin */
  GPIO_InitStruct.Pin = OI_3_Pin;
  GPIO_InitStruct.Mode = GPIO_MODE_IT_RISING;
  GPIO_InitStruct.Pull = GPIO_NOPULL;
  HAL_GPIO_Init(OI_3_GPIO_Port, &GPIO_InitStruct);

  /*Configure GPIO pin : OI_6_Pin */
  GPIO_InitStruct.Pin = OI_6_Pin;
  GPIO_InitStruct.Mode = GPIO_MODE_INPUT;
  GPIO_InitStruct.Pull = GPIO_NOPULL;
  HAL_GPIO_Init(OI_6_GPIO_Port, &GPIO_InitStruct);

  /*Configure GPIO pins : LO_4B4_Pin HO_1_Pin */
  GPIO_InitStruct.Pin = LO_4B4_Pin | HO_1_Pin;
  GPIO_InitStruct.Mode = GPIO_MODE_OUTPUT_PP;
  GPIO_InitStruct.Pull = GPIO_NOPULL;
  GPIO_InitStruct.Speed = GPIO_SPEED_FREQ_LOW;
  HAL_GPIO_Init(GPIOB, &GPIO_InitStruct);

}

void Error_Handler(void) {
  __disable_irq();
  while (1) {
  }
}
#ifdef USE_FULL_ASSERT
/**
 * @brief  Reports the name of the source file and the source line number
 *         where the assert_param error has occurred.
 * @param  file: pointer to the source file name
 * @param  line: assert_param error line source number
 * @retval None
 */
void assert_failed(uint8_t *file, uint32_t line) {
  /* USER CODE BEGIN 6 */
  /* User can add his own implementation to report the file name and line
     number, ex: printf("Wrong parameters value: file %s on line %d\r\n", file,
     line) */
  /* USER CODE END 6 */
}
#endif /* USE_FULL_ASSERT */
